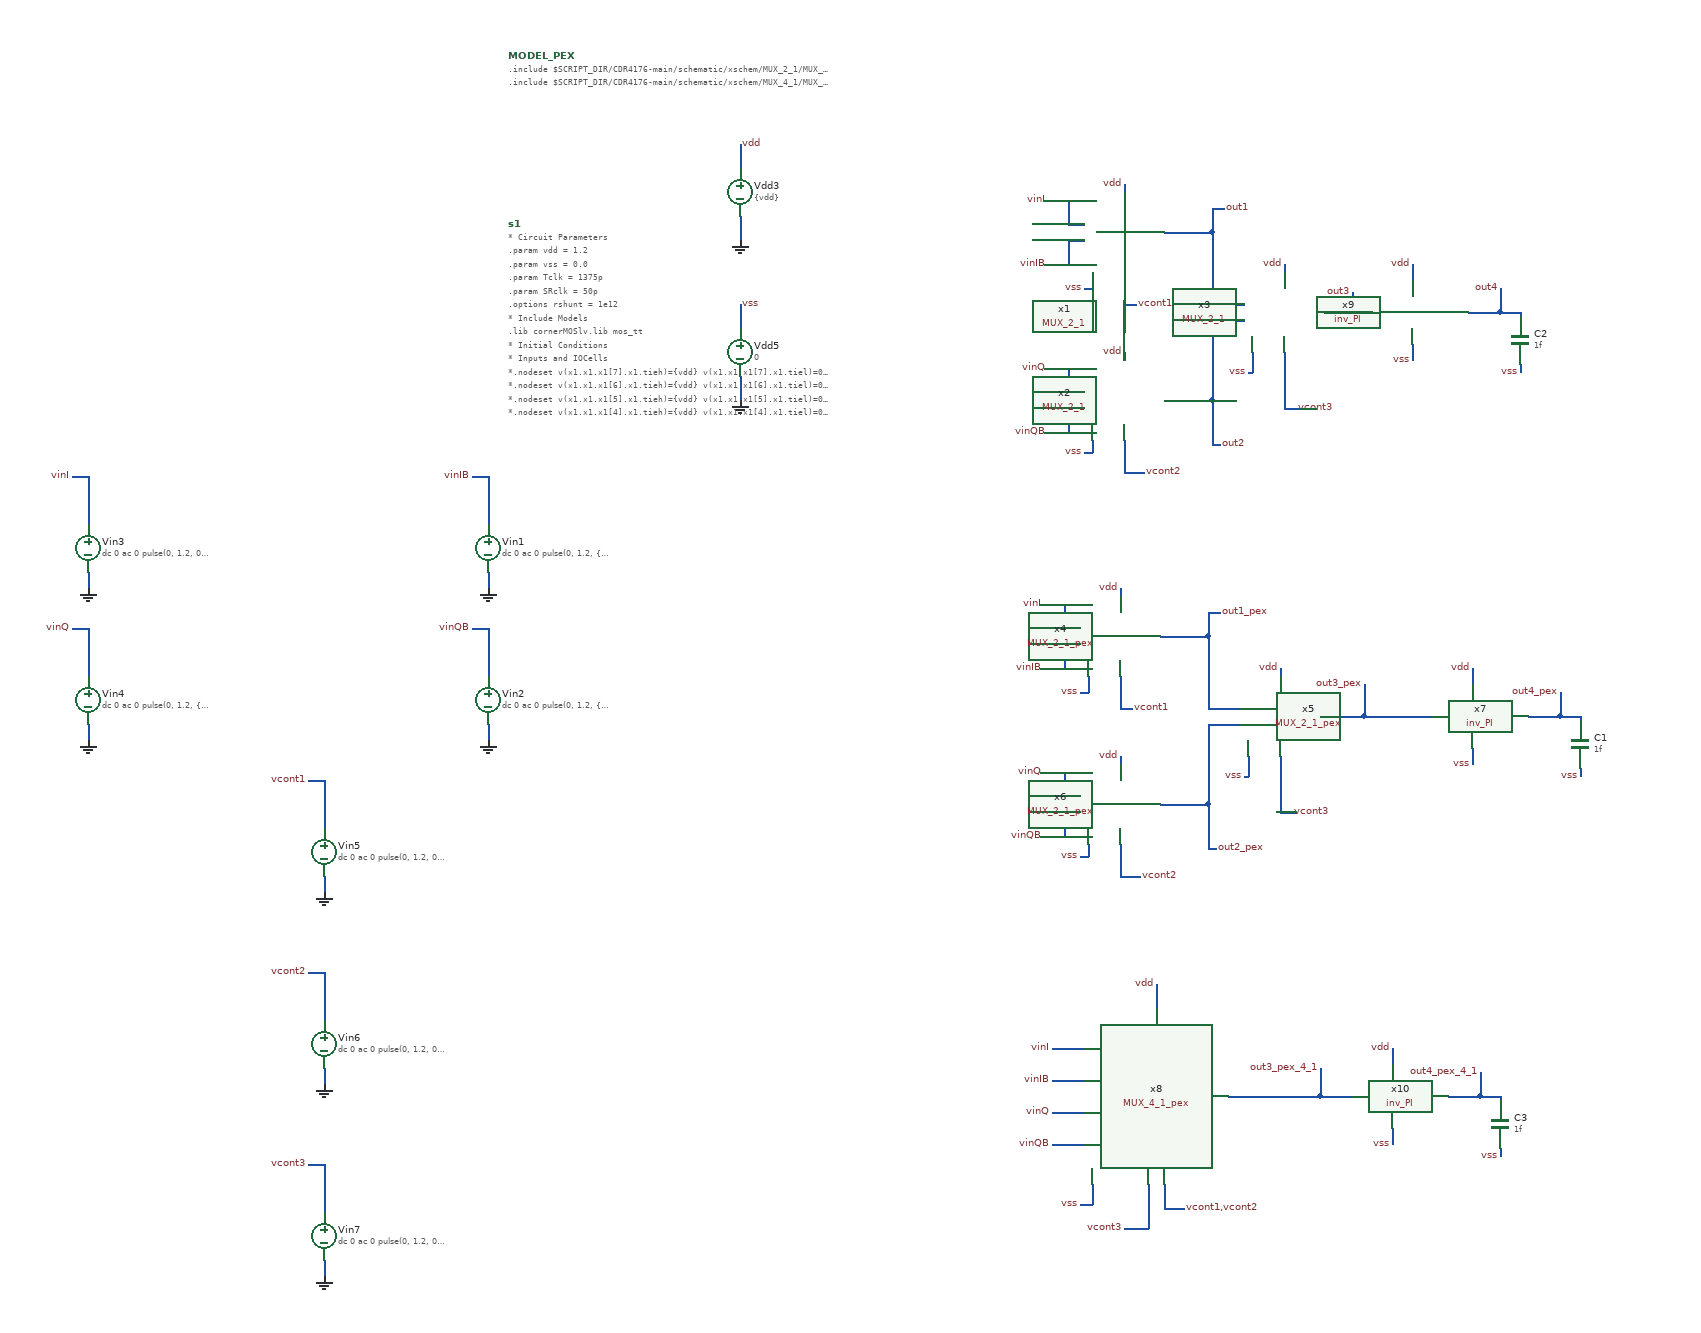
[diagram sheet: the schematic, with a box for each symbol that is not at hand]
v {xschem version=3.4.8RC file_version=1.2}
G {}
K {}
V {}
S {}
F {}
E {}
B 2 660 -635 1730 -155 {flags=graph
y2=1.543013
ypos1=0
ypos2=2
divy=5
subdivy=1
unity=1
x1=2.364394e-09
x2=8.4041934e-09
divx=5
subdivx=1
xlabmag=1.0
ylabmag=1.0
dataset=-1
unitx=1
logx=0
logy=0
hilight_wave=-1
y1=-0.05772379
color="4 5 6 10"
node="vinI
vinQ
vinIB
vinQB"}
B 2 660 -115 1730 365 {flags=graph
y2=2.1943859
ypos1=0
ypos2=2
divy=5
subdivy=1
unity=1
x1=2.364394e-09
x2=8.4041934e-09
divx=5
subdivx=1
xlabmag=1.0
ylabmag=1.0
node="out1
out1_pex"
color="4 10"
dataset=-1
unitx=1
logx=0
logy=0
hilight_wave=-1
y1=-0.017454133}
B 2 660 405 1730 885 {flags=graph
y2=1.5
ypos1=0
ypos2=2
divy=5
subdivy=1
unity=1
x1=2.364394e-09
x2=8.4041934e-09
divx=5
subdivx=1
xlabmag=1.0
ylabmag=1.0
node="out3
out3_pex
out3_pex_4_1"
color="4 12 7"
dataset=-1
unitx=1
logx=0
logy=0
hilight_wave=-1
y1=-0.1}
B 2 1770 -635 2840 -155 {flags=graph
y2=1.5
ypos1=0
ypos2=2
divy=5
subdivy=1
unity=1
x1=2.364394e-09
x2=8.4041934e-09
divx=5
subdivx=1
xlabmag=1.0
ylabmag=1.0
node="x1.tieh
x1.tiel
x2.tieh
x2.tiel"
color="4 10 12 7"
dataset=-1
unitx=1
logx=0
logy=0
hilight_wave=-1
y1=-0.1}
B 2 1760 -115 2830 365 {flags=graph
y2=1.5
ypos1=0
ypos2=2
divy=5
subdivy=1
unity=1
x1=2.364394e-09
x2=8.4041934e-09
divx=5
subdivx=1
xlabmag=1.0
ylabmag=1.0
node="out2
out2_pex"
color="4 10"
dataset=-1
unitx=1
logx=0
logy=0
hilight_wave=-1
y1=-0.1}
B 2 1760 405 2830 885 {flags=graph
y2=1.5
ypos1=0
ypos2=2
divy=5
subdivy=1
unity=1
x1=2.364394e-09
x2=8.4041934e-09
divx=5
subdivx=1
xlabmag=1.0
ylabmag=1.0
node="out4
out4_pex
out_4_pex_4_1"
color="4 10 7"
dataset=-1
unitx=1
logx=0
logy=0
hilight_wave=-1
y1=-0.1}
N 10 -480 70 -480 {lab=out1}
N 70 -480 70 -390 {lab=out1}
N 70 -390 110 -390 {lab=out1}
N 10 -270 70 -270 {lab=out2}
N 70 -370 70 -270 {lab=out2}
N 70 -370 110 -370 {lab=out2}
N -520 -500 -520 -470 {lab=GND}
N -520 -590 -520 -560 {lab=vdd}
N -520 -300 -520 -270 {lab=GND}
N -520 -390 -520 -360 {lab=vss}
N -40 -540 -40 -530 {lab=vdd}
N 160 -440 160 -430 {lab=vdd}
N -40 -330 -40 -320 {lab=vdd}
N -40 -430 -40 -390 {lab=vcont1}
N 160 -330 160 -260 {lab=vcont3}
N -110 -280 -90 -280 {lab=vinQ}
N -110 -310 -110 -280 {lab=vinQ}
N -140 -310 -110 -310 {lab=vinQ}
N -140 -230 -110 -230 {lab=vinQB}
N -110 -260 -110 -230 {lab=vinQB}
N -110 -260 -90 -260 {lab=vinQB}
N -140 -520 -110 -520 {lab=vinI}
N -110 -520 -110 -490 {lab=vinI}
N -110 -490 -90 -490 {lab=vinI}
N -110 -470 -90 -470 {lab=vinIB}
N -110 -470 -110 -440 {lab=vinIB}
N -140 -440 -110 -440 {lab=vinIB}
N -1040 325 -1040 345 {
lab=GND}
N -1040 205 -1040 265 {
lab=vcont1}
N -1060 205 -1040 205 {
lab=vcont1}
N -1040 565 -1040 585 {
lab=GND}
N -1040 445 -1040 505 {
lab=vcont2}
N -1060 445 -1040 445 {
lab=vcont2}
N -1040 805 -1040 825 {
lab=GND}
N -1040 685 -1040 745 {
lab=vcont3}
N -1060 685 -1040 685 {
lab=vcont3}
N 160 -260 180 -260 {lab=vcont3}
N -40 -180 -15 -180 {lab=vcont2}
N 70 -510 85 -510 {lab=out1}
N 70 -510 70 -480 {lab=out1}
N 70 -215 80 -215 {lab=out2}
N 70 -270 70 -215 {lab=out2}
N -1335 -55 -1335 -35 {
lab=GND}
N -1335 -175 -1335 -115 {
lab=vinI}
N -1355 -175 -1335 -175 {
lab=vinI}
N -1335 135 -1335 155 {
lab=GND}
N -1335 15 -1335 75 {
lab=vinQ}
N -1355 15 -1335 15 {
lab=vinQ}
N -835 -55 -835 -35 {
lab=GND}
N -835 -175 -835 -115 {
lab=vinIB}
N -855 -175 -835 -175 {
lab=vinIB}
N -835 15 -835 75 {
lab=vinQB}
N -855 15 -835 15 {
lab=vinQB}
N -835 135 -835 155 {
lab=GND}
N -90 -410 -80 -410 {lab=vss}
N -80 -430 -80 -410 {lab=vss}
N -40 -390 -25 -390 {lab=vcont1}
N 115 -305 120 -305 {lab=vss}
N 120 -330 120 -305 {lab=vss}
N -90 -205 -80 -205 {lab=vss}
N -80 -220 -80 -205 {lab=vss}
N -40 -220 -40 -180 {lab=vcont2}
N 5 25 65 25 {lab=out1_pex}
N 65 25 65 115 {lab=out1_pex}
N 65 115 105 115 {lab=out1_pex}
N 5 235 65 235 {lab=out2_pex}
N 65 135 65 235 {lab=out2_pex}
N 65 135 105 135 {lab=out2_pex}
N -45 -35 -45 -25 {lab=vdd}
N 155 65 155 75 {lab=vdd}
N -45 175 -45 185 {lab=vdd}
N -45 75 -45 115 {lab=vcont1}
N 155 175 155 245 {lab=vcont3}
N -115 225 -95 225 {lab=vinQ}
N -115 195 -115 225 {lab=vinQ}
N -145 195 -115 195 {lab=vinQ}
N -145 275 -115 275 {lab=vinQB}
N -115 245 -115 275 {lab=vinQB}
N -115 245 -95 245 {lab=vinQB}
N -145 -15 -115 -15 {lab=vinI}
N -115 -15 -115 15 {lab=vinI}
N -115 15 -95 15 {lab=vinI}
N -115 35 -95 35 {lab=vinIB}
N -115 35 -115 65 {lab=vinIB}
N -145 65 -115 65 {lab=vinIB}
N 155 245 175 245 {lab=vcont3}
N -45 325 -20 325 {lab=vcont2}
N 65 -5 80 -5 {lab=out1_pex}
N 65 -5 65 25 {lab=out1_pex}
N 65 290 75 290 {lab=out2_pex}
N 65 235 65 290 {lab=out2_pex}
N 260 85 260 125 {lab=out3_pex}
N 260 125 345 125 {lab=out3_pex}
N -95 95 -85 95 {lab=vss}
N -85 75 -85 95 {lab=vss}
N -45 115 -30 115 {lab=vcont1}
N 110 200 115 200 {lab=vss}
N 115 175 115 200 {lab=vss}
N -95 300 -85 300 {lab=vss}
N -85 285 -85 300 {lab=vss}
N -45 285 -45 325 {lab=vcont2}
N 245 -380 270 -380 {lab=out3}
N 320 -440 320 -420 {lab=vdd}
N 320 -340 320 -320 {lab=vss}
N 430 -380 455 -380 {lab=out4}
N 245 -405 245 -380 {lab=out3}
N 210 -380 245 -380 {lab=out3}
N 455 -380 455 -375 {lab=out4}
N 455 -315 455 -305 {lab=vss}
N 430 -410 430 -380 {lab=out4}
N 390 -380 430 -380 {lab=out4}
N 395 65 395 85 {lab=vdd}
N 395 165 395 185 {lab=vss}
N 505 125 530 125 {lab=out4_pex}
N 530 125 530 130 {lab=out4_pex}
N 530 190 530 200 {lab=vss}
N 505 95 505 125 {lab=out4_pex}
N 465 125 505 125 {lab=out4_pex}
N 205 125 260 125 {lab=out3_pex}
N 295 540 295 560 {lab=vdd}
N 295 640 295 660 {lab=vss}
N 405 600 430 600 {lab=out4_pex_4_1}
N 430 600 430 605 {lab=out4_pex_4_1}
N 430 665 430 675 {lab=vss}
N 405 570 405 600 {lab=out4_pex_4_1}
N 365 600 405 600 {lab=out4_pex_4_1}
N 0 460 -0 490 {lab=vdd}
N 205 600 245 600 {lab=out3_pex_4_1}
N 205 565 205 600 {lab=out3_pex_4_1}
N 90 600 205 600 {lab=out3_pex_4_1}
N -95 735 -80 735 {lab=vss}
N -80 710 -80 735 {lab=vss}
N 10 740 35 740 {lab=vcont1,vcont2}
N 10 710 10 740 {lab=vcont1,vcont2}
N -40 765 -10 765 {lab=vcont3}
N -10 710 -10 765 {lab=vcont3}
N -130 540 -90 540 {lab=vinI}
N -130 580 -90 580 {lab=vinIB}
N -130 620 -90 620 {lab=vinQ}
N -130 660 -90 660 {lab=vinQB}
C {devices/vsource.sym} -520 -530 0 0 {name=Vdd3 value=\{vdd\} savecurrent=false
}
C {devices/gnd.sym} -520 -470 0 0 {name=l1 lab=GND}
C {devices/lab_pin.sym} -520 -590 2 0 {name=p13 sig_type=std_logic lab=vdd}
C {devices/vsource.sym} -520 -330 0 0 {name=Vdd5 value=0 savecurrent=false
}
C {devices/gnd.sym} -520 -270 0 0 {name=l6 lab=GND
value=0}
C {devices/lab_pin.sym} -520 -390 2 0 {name=p14 sig_type=std_logic lab=vss}
C {netlist_not_shown.sym} -810 -490 0 0 {name=s1 only_toplevel=false 

value="

* Circuit Parameters
.param vdd = 1.2
.param vss = 0.0
.param Tclk = 1375p
.param SRclk = 50p
.options rshunt = 1e12


* Include Models
.lib cornerMOSlv.lib mos_tt

* 	Initial Conditions
* Inputs and IOCells
*.nodeset v(x1.x1.x1[7].x1.tieh)=\{vdd\} v(x1.x1.x1[7].x1.tiel)=0 v(x1.x1.x1[7].x3.tieh)=\{vdd\} v(x1.x1.x1[7].x3.tiel)=0 v(x1.x1.x1[7].x5.tieh)=\{vdd\} v(x1.x1.x1[7].x5.tiel)=0
*.nodeset v(x1.x1.x1[6].x1.tieh)=\{vdd\} v(x1.x1.x1[6].x1.tiel)=0 v(x1.x1.x1[6].x3.tieh)=\{vdd\} v(x1.x1.x1[6].x3.tiel)=0 v(x1.x1.x1[6].x5.tieh)=\{vdd\} v(x1.x1.x1[6].x5.tiel)=0
*.nodeset v(x1.x1.x1[5].x1.tieh)=\{vdd\} v(x1.x1.x1[5].x1.tiel)=0 v(x1.x1.x1[5].x3.tieh)=\{vdd\} v(x1.x1.x1[5].x3.tiel)=0 v(x1.x1.x1[5].x5.tieh)=\{vdd\} v(x1.x1.x1[5].x5.tiel)=0
*.nodeset v(x1.x1.x1[4].x1.tieh)=\{vdd\} v(x1.x1.x1[4].x1.tiel)=0 v(x1.x1.x1[4].x3.tieh)=\{vdd\} v(x1.x1.x1[4].x3.tiel)=0 v(x1.x1.x1[4].x5.tieh)=\{vdd\} v(x1.x1.x1[4].x5.tiel)=0
*.nodeset v(x1.x1.x1[3].x1.tieh)=\{vdd\} v(x1.x1.x1[3].x1.tiel)=0 v(x1.x1.x1[3].x3.tieh)=\{vdd\} v(x1.x1.x1[3].x3.tiel)=0 v(x1.x1.x1[3].x5.tieh)=\{vdd\} v(x1.x1.x1[3].x5.tiel)=0
*.nodeset v(x1.x1.x1[2].x1.tieh)=\{vdd\} v(x1.x1.x1[2].x1.tiel)=0 v(x1.x1.x1[2].x3.tieh)=\{vdd\} v(x1.x1.x1[2].x3.tiel)=0 v(x1.x1.x1[2].x5.tieh)=\{vdd\} v(x1.x1.x1[2].x5.tiel)=0
*.nodeset v(x1.x1.x1[1].x1.tieh)=\{vdd\} v(x1.x1.x1[1].x1.tiel)=0 v(x1.x1.x1[1].x3.tieh)=\{vdd\} v(x1.x1.x1[1].x3.tiel)=0 v(x1.x1.x1[1].x5.tieh)=\{vdd\} v(x1.x1.x1[1].x5.tiel)=0
*.nodeset v(x1.x1.x1[0].x1.tieh)=\{vdd\} v(x1.x1.x1[0].x1.tiel)=0 v(x1.x1.x1[0].x3.tieh)=\{vdd\} v(x1.x1.x1[0].x3.tiel)=0 v(x1.x1.x1[0].x5.tieh)=\{vdd\} v(x1.x1.x1[0].x5.tiel)=0
*.nodeset v(x2.x1.x1[7].x1.tieh)=\{vdd\} v(x2.x1.x1[7].x1.tiel)=0 v(x2.x1.x1[7].x3.tieh)=\{vdd\} v(x2.x1.x1[7].x3.tiel)=0 v(x2.x1.x1[7].x5.tieh)=\{vdd\} v(x2.x1.x1[7].x5.tiel)=0
*.nodeset v(x2.x1.x1[6].x1.tieh)=\{vdd\} v(x2.x1.x1[6].x1.tiel)=0 v(x2.x1.x1[6].x3.tieh)=\{vdd\} v(x2.x1.x1[6].x3.tiel)=0 v(x2.x1.x1[6].x5.tieh)=\{vdd\} v(x2.x1.x1[6].x5.tiel)=0
*.nodeset v(x2.x1.x1[5].x1.tieh)=\{vdd\} v(x2.x1.x1[5].x1.tiel)=0 v(x2.x1.x1[5].x3.tieh)=\{vdd\} v(x2.x1.x1[5].x3.tiel)=0 v(x2.x1.x1[5].x5.tieh)=\{vdd\} v(x2.x1.x1[5].x5.tiel)=0
*.nodeset v(x2.x1.x1[4].x1.tieh)=\{vdd\} v(x2.x1.x1[4].x1.tiel)=0 v(x2.x1.x1[4].x3.tieh)=\{vdd\} v(x2.x1.x1[4].x3.tiel)=0 v(x2.x1.x1[4].x5.tieh)=\{vdd\} v(x2.x1.x1[4].x5.tiel)=0
*.nodeset v(x2.x1.x1[3].x1.tieh)=\{vdd\} v(x2.x1.x1[3].x1.tiel)=0 v(x2.x1.x1[3].x3.tieh)=\{vdd\} v(x2.x1.x1[3].x3.tiel)=0 v(x2.x1.x1[3].x5.tieh)=\{vdd\} v(x2.x1.x1[3].x5.tiel)=0
*.nodeset v(x2.x1.x1[2].x1.tieh)=\{vdd\} v(x2.x1.x1[2].x1.tiel)=0 v(x2.x1.x1[2].x3.tieh)=\{vdd\} v(x2.x1.x1[2].x3.tiel)=0 v(x2.x1.x1[2].x5.tieh)=\{vdd\} v(x2.x1.x1[2].x5.tiel)=0
*.nodeset v(x2.x1.x1[1].x1.tieh)=\{vdd\} v(x2.x1.x1[1].x1.tiel)=0 v(x2.x1.x1[1].x3.tieh)=\{vdd\} v(x2.x1.x1[1].x3.tiel)=0 v(x2.x1.x1[1].x5.tieh)=\{vdd\} v(x2.x1.x1[1].x5.tiel)=0
*.nodeset v(x2.x1.x1[0].x1.tieh)=\{vdd\} v(x2.x1.x1[0].x1.tiel)=0 v(x2.x1.x1[0].x3.tieh)=\{vdd\} v(x2.x1.x1[0].x3.tiel)=0 v(x2.x1.x1[0].x5.tieh)=\{vdd\} v(x2.x1.x1[0].x5.tiel)=0


* OP Parameters & Singals to save
.save v(vinI) v(vinQ) v(vinIB) v(vinQB) v(out1) v(out2) v(out3) v(out4) v(out1_pex) v(out2_pex) v(out3_pex) v(out4_pex) v(out3_pex_4_1) v(out4_pex_4_1) v(x1.tieh) v(x1.tiel) v(x2.tieh) v(x2.tiel) v(vcont1) v(vcont2) v(vcont3)

*Simulations
.control
*set output_path = tb_linearity_8xpi/
	*set ngdebug
	*set verbose
	tran 5PS 16NS
	*display
	*set filetype = ascii
        write tran_mux_2_1_pex.raw
	set filetype = ascii
        write tran_mux_2_1_pex_ascii.raw
	*V(vout) V(vout8i) V(vinI) V(vinIB) V(@x1.vsq[2]) V(x1.vst[7]) V(x1.vstq[7]) V(x1.x1.vini) V(x1.x1.vinib) V(x1.x1.vinq) V(x1.x1.vinqb)
	*write \{$output_path\}tran_linearity_termoless.raw V(Vout) V(Vout8I) V(vinI) V(VoutI1) V(VoutI2) V(VoutQ1) V(VoutIB1) V(VoutQB1)
.endc
.end"}
C {devices/lab_pin.sym} -135 -520 0 0 {name=p4 sig_type=std_logic lab=vinI}
C {devices/lab_pin.sym} -135 -440 0 0 {name=p5 sig_type=std_logic lab=vinIB}
C {devices/lab_pin.sym} -135 -310 0 0 {name=p6 sig_type=std_logic lab=vinQ}
C {devices/lab_pin.sym} -135 -230 0 0 {name=p7 sig_type=std_logic lab=vinQB}
C {devices/lab_pin.sym} -40 -540 1 0 {name=p8 sig_type=std_logic lab=vdd}
C {devices/lab_pin.sym} 160 -440 1 0 {name=p9 sig_type=std_logic lab=vdd}
C {devices/lab_pin.sym} -40 -330 1 0 {name=p10 sig_type=std_logic lab=vdd}
C {devices/lab_pin.sym} -90 -410 0 0 {name=p11 sig_type=std_logic lab=vss}
C {devices/lab_pin.sym} 115 -305 0 0 {name=p12 sig_type=std_logic lab=vss}
C {devices/lab_pin.sym} -90 -205 0 0 {name=p15 sig_type=std_logic lab=vss}
C {devices/gnd.sym} -1040 345 0 0 {name=l7 lab=GND}
C {devices/vsource.sym} -1040 295 0 0 {name=Vin5 value="dc 0 ac 0 pulse(0, 1.2, 0, \{SRclk\}, \{SRclk\}, \{3*Tclk-SRclk\}, \{6*Tclk\}) "}
C {devices/lab_pin.sym} -1060 205 0 0 {name=p16 sig_type=std_logic lab=vcont1}
C {devices/gnd.sym} -1040 585 0 0 {name=l8 lab=GND}
C {devices/vsource.sym} -1040 535 0 0 {name=Vin6 value="dc 0 ac 0 pulse(0, 1.2, 0, \{SRclk\}, \{SRclk\}, \{3*Tclk-SRclk\}, \{6*Tclk\}) "}
C {devices/lab_pin.sym} -1060 445 0 0 {name=p18 sig_type=std_logic lab=vcont2}
C {devices/gnd.sym} -1040 825 0 0 {name=l9 lab=GND}
C {devices/vsource.sym} -1040 775 0 0 {name=Vin7 value="dc 0 ac 0 pulse(0, 1.2, 0, \{SRclk\}, \{SRclk\}, \{6*Tclk-SRclk\}, \{12*Tclk\}) "}
C {devices/lab_pin.sym} -1060 685 0 0 {name=p19 sig_type=std_logic lab=vcont3}
C {devices/lab_pin.sym} -25 -390 2 0 {name=p20 sig_type=std_logic lab=vcont1}
C {devices/lab_pin.sym} -15 -180 2 0 {name=p21 sig_type=std_logic lab=vcont2}
C {devices/lab_pin.sym} 175 -260 2 0 {name=p22 sig_type=std_logic lab=vcont3}
C {devices/lab_pin.sym} 85 -510 2 0 {name=p23 sig_type=std_logic lab=out1}
C {devices/lab_pin.sym} 80 -215 2 0 {name=p24 sig_type=std_logic lab=out2}
C {devices/gnd.sym} -1335 -35 0 0 {name=l2 lab=GND}
C {devices/vsource.sym} -1335 -85 0 0 {name=Vin3 value="dc 0 ac 0 pulse(0, 1.2, 0, \{SRclk\}, \{SRclk\}, \{Tclk/2-SRclk\}, \{Tclk\}) "}
C {devices/lab_pin.sym} -1355 -175 0 0 {name=p1 sig_type=std_logic lab=vinI}
C {devices/lab_pin.sym} -1355 15 0 0 {name=p2 sig_type=std_logic lab=vinQ}
C {devices/vsource.sym} -1335 105 0 0 {name=Vin4 value="dc 0 ac 0 pulse(0, 1.2, \{Tclk/4\}, \{SRclk\}, \{SRclk\}, \{Tclk/2-SRclk\}, \{Tclk\}) "}
C {devices/gnd.sym} -835 -35 0 0 {name=l4 lab=GND}
C {devices/vsource.sym} -835 -85 0 0 {name=Vin1 value="dc 0 ac 0 pulse(0, 1.2, \{Tclk/2\}, \{SRclk\}, \{SRclk\}, \{Tclk/2-SRclk\}, \{Tclk\}) "}
C {devices/lab_pin.sym} -855 -175 0 0 {name=p3 sig_type=std_logic lab=vinIB}
C {devices/vsource.sym} -835 105 0 0 {name=Vin2 value="dc 0 ac 0 pulse(0, 1.2, \{3*Tclk/4\}, \{SRclk\}, \{SRclk\}, \{Tclk/2-SRclk\}, \{Tclk\} ) "}
C {devices/lab_pin.sym} -855 15 0 0 {name=p17 sig_type=std_logic lab=vinQB}
C {devices/gnd.sym} -1335 155 0 0 {name=l3 lab=GND}
C {devices/gnd.sym} -835 155 0 0 {name=l5 lab=GND}
C {devices/launcher.sym} 725 935 0 0 {name=h5
descr="load waves Ctrl + left click" 
tclcommand="xschem raw_read [file join $netlist_dir tran_mux_2_1_pex.raw] tran"
}
C {MUX_2_1/MUX_2_1.sym} -120 -400 0 0 {name=x1}
C {MUX_2_1/MUX_2_1.sym} 80 -300 0 0 {name=x3}
C {MUX_2_1/MUX_2_1.sym} -120 -190 0 0 {name=x2}
C {devices/lab_pin.sym} -140 -15 0 0 {name=p26 sig_type=std_logic lab=vinI}
C {devices/lab_pin.sym} -140 65 0 0 {name=p27 sig_type=std_logic lab=vinIB}
C {devices/lab_pin.sym} -140 195 0 0 {name=p28 sig_type=std_logic lab=vinQ}
C {devices/lab_pin.sym} -140 275 0 0 {name=p29 sig_type=std_logic lab=vinQB}
C {devices/lab_pin.sym} -45 -35 1 0 {name=p30 sig_type=std_logic lab=vdd}
C {devices/lab_pin.sym} 155 65 1 0 {name=p31 sig_type=std_logic lab=vdd}
C {devices/lab_pin.sym} -45 175 1 0 {name=p32 sig_type=std_logic lab=vdd}
C {devices/lab_pin.sym} -95 95 0 0 {name=p33 sig_type=std_logic lab=vss}
C {devices/lab_pin.sym} 110 200 0 0 {name=p34 sig_type=std_logic lab=vss}
C {devices/lab_pin.sym} -95 300 0 0 {name=p35 sig_type=std_logic lab=vss}
C {devices/lab_pin.sym} -30 115 2 0 {name=p36 sig_type=std_logic lab=vcont1}
C {devices/lab_pin.sym} -20 325 2 0 {name=p37 sig_type=std_logic lab=vcont2}
C {devices/lab_pin.sym} 170 245 2 0 {name=p38 sig_type=std_logic lab=vcont3}
C {devices/lab_pin.sym} 80 -5 2 0 {name=p39 sig_type=std_logic lab=out1_pex}
C {devices/lab_pin.sym} 75 290 2 0 {name=p40 sig_type=std_logic lab=out2_pex}
C {devices/lab_pin.sym} 260 85 1 0 {name=p41 sig_type=std_logic lab=out3_pex}
C {MUX_2_1/MUX_2_1_pex.sym} -45 25 0 0 {name=x4}
C {MUX_2_1/MUX_2_1_pex.sym} 155 125 0 0 {name=x5}
C {MUX_2_1/MUX_2_1_pex.sym} -45 235 0 0 {name=x6}
C {inv_PI/inv_PI.sym} 230 -240 0 0 {name=x9}
C {devices/lab_pin.sym} 320 -440 1 0 {name=p42 sig_type=std_logic lab=vdd}
C {devices/lab_pin.sym} 320 -320 3 0 {name=p43 sig_type=std_logic lab=vss}
C {devices/lab_pin.sym} 245 -405 1 0 {name=p25 sig_type=std_logic lab=out3}
C {devices/lab_pin.sym} 455 -305 3 0 {name=p44 sig_type=std_logic lab=vss}
C {capa.sym} 455 -345 0 0 {name=C2
m=1
value=1f
footprint=1206
device="ceramic capacitor"
}
C {devices/lab_pin.sym} 430 -410 1 0 {name=p45 sig_type=std_logic lab=out4}
C {inv_PI/inv_PI.sym} 305 265 0 0 {name=x7}
C {devices/lab_pin.sym} 395 65 1 0 {name=p46 sig_type=std_logic lab=vdd}
C {devices/lab_pin.sym} 395 185 3 0 {name=p47 sig_type=std_logic lab=vss}
C {devices/lab_pin.sym} 530 200 3 0 {name=p49 sig_type=std_logic lab=vss}
C {capa.sym} 530 160 0 0 {name=C1
m=1
value=1f
footprint=1206
device="ceramic capacitor"
}
C {devices/lab_pin.sym} 505 95 1 0 {name=p50 sig_type=std_logic lab=out4_pex}
C {MUX_4_1/MUX_4_1_pex.sym} 0 600 0 0 {name=x8}
C {inv_PI/inv_PI.sym} 205 740 0 0 {name=x10}
C {devices/lab_pin.sym} 295 540 1 0 {name=p48 sig_type=std_logic lab=vdd}
C {devices/lab_pin.sym} 295 660 3 0 {name=p51 sig_type=std_logic lab=vss}
C {devices/lab_pin.sym} 430 675 3 0 {name=p52 sig_type=std_logic lab=vss}
C {capa.sym} 430 635 0 0 {name=C3
m=1
value=1f
footprint=1206
device="ceramic capacitor"
}
C {devices/lab_pin.sym} 405 570 1 0 {name=p53 sig_type=std_logic lab=out4_pex_4_1}
C {devices/lab_pin.sym} 0 460 1 0 {name=p54 sig_type=std_logic lab=vdd}
C {devices/lab_pin.sym} 205 565 1 0 {name=p55 sig_type=std_logic lab=out3_pex_4_1}
C {devices/lab_pin.sym} -95 735 0 0 {name=p56 sig_type=std_logic lab=vss}
C {devices/lab_pin.sym} 35 740 2 0 {name=p57 sig_type=std_logic lab="vcont1,vcont2"}
C {devices/lab_pin.sym} -40 765 0 0 {name=p58 sig_type=std_logic lab=vcont3}
C {devices/lab_pin.sym} -130 540 0 0 {name=p59 sig_type=std_logic lab=vinI}
C {devices/lab_pin.sym} -130 580 0 0 {name=p60 sig_type=std_logic lab=vinIB}
C {devices/lab_pin.sym} -130 620 0 0 {name=p61 sig_type=std_logic lab=vinQ}
C {devices/lab_pin.sym} -130 660 0 0 {name=p62 sig_type=std_logic lab=vinQB}
C {devices/code_shown.sym} -810 -700 0 0 {name=MODEL_PEX only_toplevel=true
format="tcleval( @value )"
value="
.include \"$SCRIPT_DIR/CDR4176-main/schematic/xschem/MUX_2_1/MUX_2_1_pex.spice\"
.include \"$SCRIPT_DIR/CDR4176-main/schematic/xschem/MUX_4_1/MUX_4_1_pex.spice\"
"}
